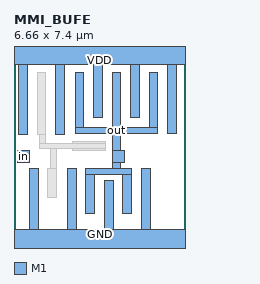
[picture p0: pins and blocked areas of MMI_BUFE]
MACRO MMI_BUFE
	CLASS CORE ;
	FOREIGN MMI_BUFE 0 0 ;
	SIZE 6.66 BY 7.4 ;
	SYMMETRY X Y ;
	SITE CORE1 ;
	PIN out
		DIRECTION output ;
		USE SIGNAL ;
		PORT
			LAYER M1 ;
			RECT 2.38 4.445 2.72 6.59 ;
			LAYER M1 ;
			RECT 3.82 4.445 4.16 6.59 ;
			LAYER M1 ;
			RECT 5.26 4.445 5.6 6.59 ;
			LAYER M1 ;
			RECT 2.38 4.215 5.6 4.445 ;
			LAYER M1 ;
			RECT 3.82 3.555 4.16 4.215 ;
			LAYER M1 ;
			RECT 3.82 3.105 4.295 3.555 ;
			LAYER M1 ;
			RECT 3.82 2.875 4.16 3.105 ;
			LAYER M1 ;
			RECT 2.8 2.645 4.58 2.875 ;
			LAYER M1 ;
			RECT 2.8 1.115 3.14 2.645 ;
			LAYER M1 ;
			RECT 4.24 1.115 4.58 2.645 ;
		END
		AntennaDiffArea 5.9643 ;
	END out
	PIN GND
		DIRECTION inout ;
		USE GROUND ;
		PORT
			LAYER M1 ;
			RECT 0.6 0.5 0.94 2.875 ;
			LAYER M1 ;
			RECT 2.08 0.5 2.42 2.875 ;
			LAYER M1 ;
			RECT 3.52 0.5 3.86 2.395 ;
			LAYER M1 ;
			RECT 4.96 0.5 5.3 2.875 ;
			LAYER M1 ;
			RECT 0 -0.5 6.66 0.5 ;
		END
	END GND
	PIN VDD
		DIRECTION inout ;
		USE POWER ;
		PORT
			LAYER M1 ;
			RECT 0 6.9 6.66 7.9 ;
			LAYER M1 ;
			RECT 0.18 4.19 0.52 6.9 ;
			LAYER M1 ;
			RECT 1.62 4.19 1.96 6.9 ;
			LAYER M1 ;
			RECT 3.1 4.835 3.44 6.9 ;
			LAYER M1 ;
			RECT 4.54 4.835 4.88 6.9 ;
			LAYER M1 ;
			RECT 5.98 4.215 6.32 6.9 ;
		END
	END VDD
	PIN in
		DIRECTION input ;
		USE SIGNAL ;
		PORT
			LAYER M1 ;
			RECT 0.145 3.105 0.595 3.555 ;
		END
		AntennaGateArea 1.3392 ;
	END in
	OBS
		LAYER M1 ;
		RECT 0.9 4.19 1.24 6.59 ;
		LAYER M1 ;
		RECT 1.01 3.855 1.24 4.19 ;
		LAYER M1 ;
		RECT 2.285 3.855 3.565 3.91 ;
		LAYER M1 ;
		RECT 1.01 3.625 3.565 3.855 ;
		LAYER M1 ;
		RECT 1.43 2.875 1.66 3.625 ;
		LAYER M1 ;
		RECT 2.285 3.57 3.565 3.625 ;
		LAYER M1 ;
		RECT 1.32 1.715 1.66 2.875 ;
	END
END MMI_BUFE
